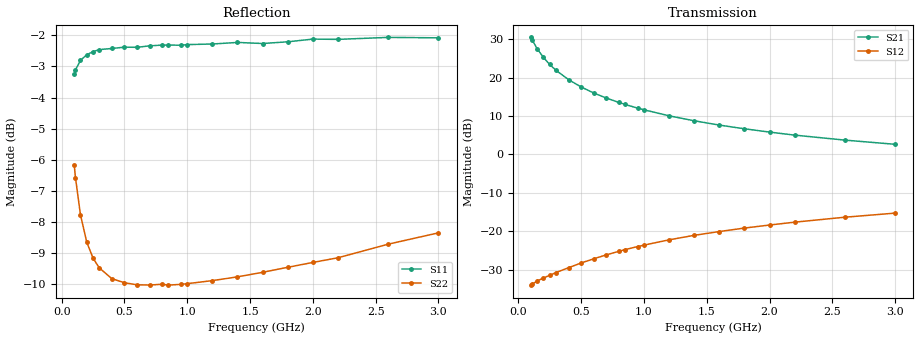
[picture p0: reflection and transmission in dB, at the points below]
! BFQ196 random sample data
!  VCE=  8.00V, IC= 50.00mA
#  GHz  S  MA  R  50
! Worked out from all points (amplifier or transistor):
!   30 points, 100 MHz to 3 GHz, reference 50 ohm
!   highest |S21| = 30.5 dB at 100 MHz (marker M1)
!   |S21| within 3 dB of that: start of sweep to 151.1 MHz
!   unconditionally stable (mu >= 1): 768.1 MHz to end of sweep
!   at 300 MHz: K = 0.73, MSG = 26.4 dB, |S12| = -30.8 dB
!   at 1.2 GHz: K = 1.05, MAG = 14.8 dB, |S12| = -22.3 dB
!   at 3 GHz: K = 1.04, MAG = 7.8 dB, |S12| = -15.3 dB
!   S11 on the Smith chart (normalised r, x): 100 MHz: 0.21, -0.33; 200 MHz: 0.15, -0.15; 500 MHz: 0.14, +0.01; 1.2 GHz: 0.13, +0.17; 2.2 GHz: 0.14, +0.35; 3 GHz: 0.15, +0.50
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0.1  0.6876 -141.8  33.66 114.7  0.0198 42.5  0.4916 -94.5
0.11  0.6991 -145.1  31.2 112.4  0.0204 42.0  0.4689 -99.2
0.15  0.7242 -155.0  23.97 105.5  0.0224 41.4  0.4084 -114.1
0.2  0.7392 -162.7  18.41 99.8  0.0245 42.4  0.369 -127.2
0.25  0.748 -167.7  14.93 95.8  0.0266 44.5  0.3479 -136.4
0.3  0.7535 -171.3  12.53 92.7  0.0289 46.4  0.3355 -143.3
0.4  0.7568 -176.9  9.464 87.8  0.0334 50.3  0.3224 -152.9
0.5  0.7604 179.1  7.599 84.0  0.0385 53.2  0.3176 -159.3
0.6  0.76 175.7  6.345 80.6  0.0436 55.1  0.3152 -164.1
0.7  0.7641 172.9  5.448 77.5  0.0491 56.4  0.3149 -167.8
0.8  0.7663 170.1  4.779 74.8  0.0546 57.3  0.3158 -170.7
0.85  0.7664 169.0  4.495 73.4  0.0575 57.3  0.3148 -171.9
0.95  0.7659 166.5  4.025 70.7  0.063 57.6  0.3157 -174.4
1  0.7677 165.2  3.826 69.3  0.0658 57.5  0.3165 -175.5
1.2  0.7694 160.7  3.198 64.3  0.0771 57.0  0.3201 -178.9
1.4  0.7739 156.4  2.754 59.4  0.0883 56.0  0.3246 177.8
1.6  0.7708 152.6  2.419 54.6  0.0989 54.5  0.3301 175.2
1.8  0.7757 148.6  2.164 50.2  0.1098 52.8  0.3363 172.7
2  0.7835 144.4  1.96 45.6  0.1203 50.9  0.3424 170.3
2.2  0.7827 140.9  1.789 41.4  0.1311 49.0  0.3484 168.1
2.6  0.7885 133.1  1.54 32.7  0.1521 44.9  0.3664 164.2
3  0.7872 125.8  1.358 24.5  0.172 40.5  0.3821 160.0
